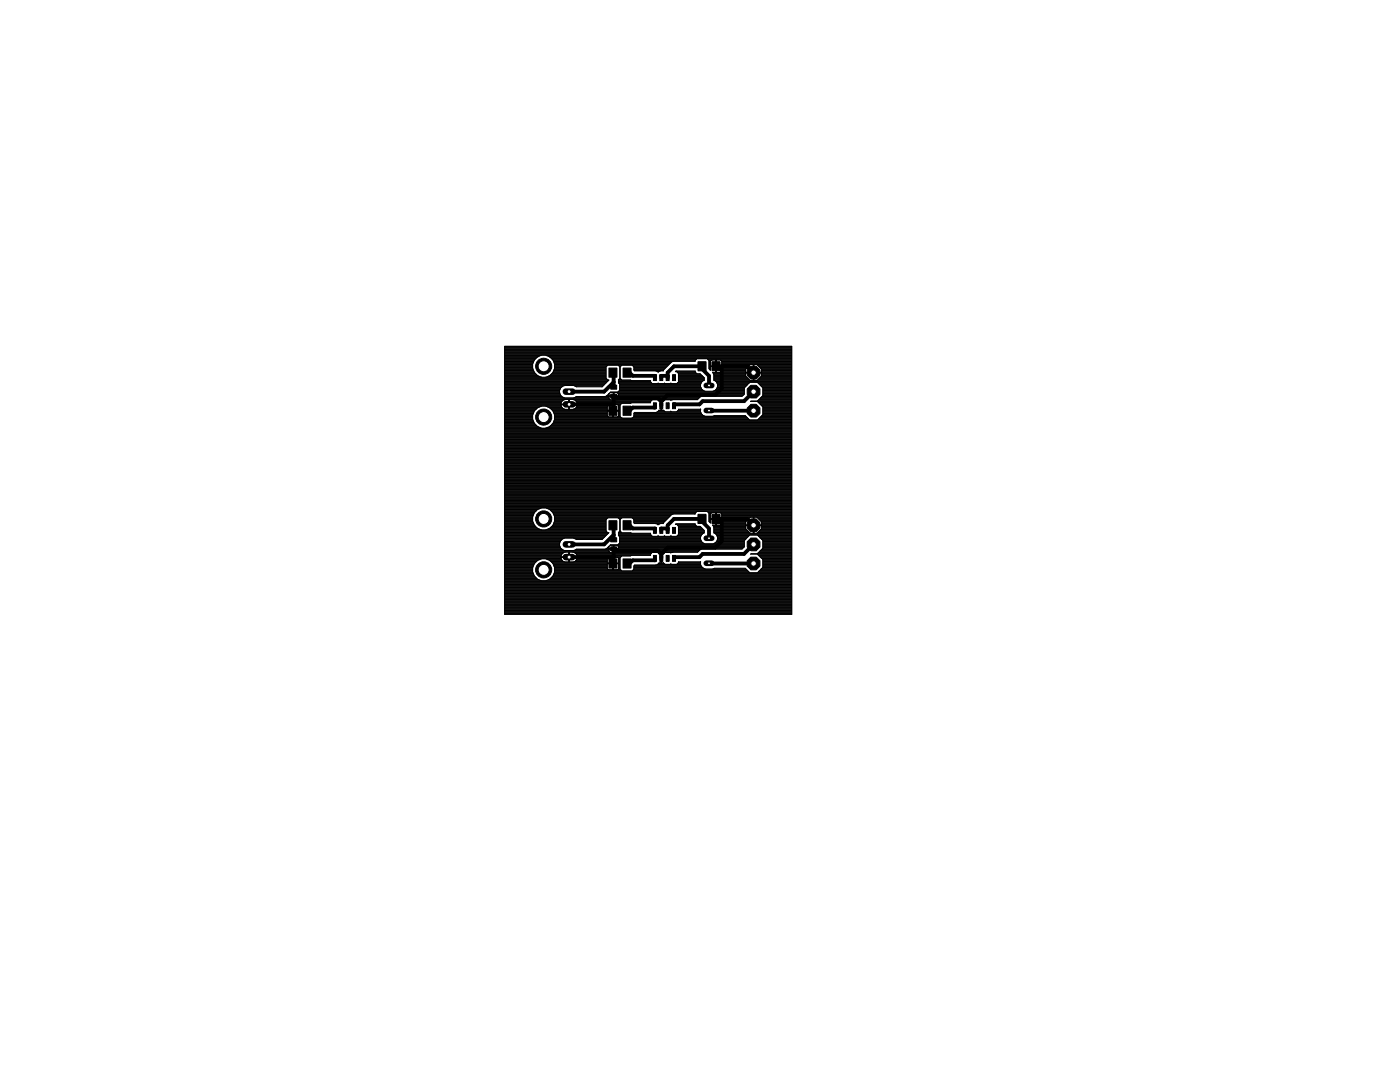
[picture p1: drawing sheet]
<svg xmlns="http://www.w3.org/2000/svg" width="279mm" height="216mm" viewBox="0 0 279 216" stroke-linecap="round" stroke-linejoin="round" font-family="sans-serif">
<g fill="#000" stroke="#000" stroke-width=".2">
<path d="M121.5 73.4h1.6v1.9h-1.6zM121.9 78.7h1.2v.8h-1.2zM121.9 76.9h1.2v.8h-1.2zM124.3 73.4h1.6v1.9h-1.6zM130.4 74.8h.6v1.1h-.6zM131.7 74.8h.6v1.1h-.6zM132.9 74.8h.6v1.1h-.6zM134.2 74.8h.6v1.1h-.6zM139.3 72.2h1.6v1.8h-1.6zM142.1 72.2h1.6v1.8h-1.6zM121.5 81h1.6v1.9h-1.6zM124.3 81h1.6v1.9h-1.6z"/>
<path d="M130.4 80.4h.6v1.2h-.6zM131.7 80.4h.6v1.2h-.6zM132.9 80.4h.6v1.2h-.6zM134.2 80.4h.6v1.2h-.6zM121.5 103.9h1.6v1.8h-1.6zM121.5 111.5h1.6v1.8h-1.6zM121.9 109.1h1.2v.8h-1.2zM121.9 107.3h1.2v.8h-1.2zM124.3 103.9h1.6v1.8h-1.6zM124.3 111.5h1.6v1.8h-1.6zM130.4 110.8h.6v1.2h-.6zM130.4 105.2h.6v1.2h-.6z"/>
<path d="M131.7 110.8h.6v1.2h-.6zM131.7 105.2h.6v1.2h-.6zM132.9 110.8h.6v1.2h-.6zM132.9 105.2h.6v1.2h-.6zM134.2 110.8h.6v1.2h-.6zM134.2 105.2h.6v1.2h-.6zM139.3 102.6h1.6v1.9h-1.6zM142.1 102.6h1.6v1.9h-1.6z"/>
<circle cx="150.4" cy="82" r="1.38"/>
</g>
<g fill="none" stroke="#000" stroke-width=".76">
<path d="M122.3 74.4h.2v2.9M122.5 79.1v2.9h-.2M122.5 79.4h8.8l.7 .7M122.5 76.3l-1.9 1.8h-7M125.1 74.4h.5l.7 .6h4.4v.4M133.2 75h-1.2v.4M139.6 73.1l1.9 1.9v1.9M140.1 73.1h-5.6l-1.3 1.3v1M142.9 73.1h6.2l1.3 1.3M144 73.1v4.4l-1.2 1.3h-9.6l-1.2 1.3M150.4 78.1l-1.9 2h-8.3l-.6 .6h-5.1v.3M113.6 80.7h8.9"/>
<path d="M130.7 81v.3h-4.4l-.7 .7h-.5M132 80.1v.9M141.5 81.9l8.9 .1M113.6 111.2h8.9M122.3 104.8h.2v2.9M122.5 109.5v2.9h-.2M122.5 109.9h8.8l.7 .6M122.5 106.7l-1.9 1.9h-7M125.1 104.8h.5l.7 .7h4.4v.3M130.7 111.4v.4h-4.4l-.7 .6h-.5M132 110.5v.9M133.2 105.5h-1.2v.3"/>
<path d="M139.6 103.5l1.9 2v1.9M140.1 103.5h-5.6l-1.3 1.3v1M141.5 112.4h8.9M142.9 103.5h6.2l1.3 1.3M144 103.5v4.5l-1.2 1.3h-9.6l-1.2 1.2M150.4 108.6l-1.9 1.9h-8.3l-.6 .7h-5.1v.2"/>
</g>
<g fill="none" stroke="#000" stroke-width=".2">
<path d="M100.7 69.1h57.3v53.5h-57.3zM100.7 79.7h12.1M100.7 73h5.6M100.7 74.1h5.8M100.7 72.9h5.6M100.7 74.2h5.9M100.7 74.3h5.9M100.7 72.7h5.6M100.7 74.4h6M100.7 75.3h20.2M100.7 79h11.3M100.7 79.1h11.4"/>
<path d="M100.7 77.2h11.4M100.7 80h11.6M100.7 79.8h11.7M100.7 79.6h20.9M100.7 79.5h20.8M100.7 79.4h11.9M100.7 79.2h11.6M100.7 78.9h11.2M100.7 78.8h11.1M100.7 78.6h11.1M100.7 78.5h11M100.7 78.4h11"/>
<path d="M100.7 78.3h11M100.7 78.2h11M100.7 78h11M100.7 77.9h11M100.7 77.8h11M100.7 77.7h11.1M100.7 77.6h11.1M100.7 77.4h11.2M100.7 77.3h11.3M100.7 77.1h11.6M100.7 77h11.9M100.7 76.8h19.8"/>
<path d="M100.7 76.7h19.9M100.7 76.6h20.1M100.7 76.5h20.2M100.7 76.3h20.3M100.7 76.2h20.4M100.7 76.1h20.5M100.7 76h20.7M100.7 75.8h20.5M100.7 75.6h20.4M100.7 75.5h20.3M100.7 75.4h20.2M100.7 75.1h7.1"/>
<path d="M100.7 75h6.8M100.7 74.9h6.5M100.7 74.8h6.4M100.7 74.7h6.3M100.7 74.5h6.1M100.7 73.9h5.8M100.7 73.8h5.7M100.7 73.7h5.7M100.7 73.6h5.6M100.7 73.4h5.6M100.7 73.3h5.6M100.7 73.2h5.6"/>
<path d="M100.7 73.1h5.6M100.7 72.6h5.6M100.7 72.5h5.7M100.7 72.4h5.7M100.7 72.2h5.8M100.7 72.1h5.8M100.7 72h5.9M100.7 71.9h5.9M100.7 71.8h6M100.7 71.6h6.1M100.7 71.5h6.3M100.7 71.4h6.4"/>
<path d="M100.7 71.3h6.5M100.7 71.2h6.7M100.7 71h7M100.7 70.9h7.3M100.7 70.8h57.3M100.7 70.7h57.3M100.7 70.6h57.3M100.7 70.4h57.3M100.7 70.3h57.3M100.7 70.2h57.3M100.7 70.1h57.3M100.7 70h57.3"/>
<path d="M100.7 69.8h57.3M100.7 69.7h57.3M100.7 69.6h57.3M100.7 69.5h57.3M100.7 69.4h57.3M100.7 69.2h57.3M108.1 75.3a2.23 2.23 0 0 1-1.5-3.5 2.23 2.23 0 0 1 3.7 0 2.23 2.23 0 0 1-1.4 3.5M109 70.9h49M109.2 75.1h11.7M109.3 71h48.7M109.5 75h11.4M109.6 71.2h48.4"/>
<path d="M109.8 74.9h11.1M109.8 71.3h48.2M109.9 74.8h11M109.9 71.4h48.1M110 74.7h10.9M110 71.5h48M110.1 74.5h10.8M110.2 71.6h28.8M110.3 74.4h10.6M110.3 71.8h28.6M110.4 74.3h10.5M110.4 71.9h28.4"/>
<path d="M110.4 74.2h10.5M110.4 72h28.3M110.5 74.1h10.4M110.5 72.1h23.8M110.5 73.9h10.4M110.5 72.2h23.5M110.6 73.8h10.3M110.6 72.4h23.3M110.6 73.7h10.3M110.6 72.5h23.2M110.7 73.6h10.2M110.7 73h10.5"/>
<path d="M110.7 72.9h22.7M110.7 72.7h22.8M110.7 73.4h10.2M110.7 73.3h10.2M110.7 73.2h10.2M110.7 73.1h10.4M110.7 72.6h22.9M111.7 77.9v.5M111.7 78.4l.2 .5 .8 .5h1.8l.5-.3h25M113.5 79.7v2M113.5 80h.1M113.5 79.8h.1"/>
<path d="M113.6 79.7v2M114.4 79.7h7.3M114.6 79.4h6.9M114.6 77h5.8M114.7 79.8l-1.9-.1-.6 .4M114.7 79.8l.3 .3M114.7 79.8h15.4M114.9 79.2h6.6M114.9 77.1h5.4M114.9 80h15.1M120.9 73.2v2.3l.4 .3M121 79h27.2"/>
<path d="M121.2 78.9h.3M121.3 72.9l-.4 .3M121.3 78.8h.2M121.4 78.6h.1M121.5 75.8v.1M121.5 75.8l-20.8 .1M121.5 75.9l-1.3 1.3h-5.2l-.5-.3h-1.8l-.8 .5-.2 .5M121.5 78.6v.4M121.5 79.1v.4M121.5 79.5l.2 .2M121.6 78.5l-.8 .6M121.6 78.5h.1"/>
<path d="M121.6 78.5l-.1 .1M121.7 78.4l.7-.1v1.5l-.7-.1M121.7 78.4h.1M121.8 78.3h26.7M122.4 79.7h.1M122.4 79.6h.1M122.4 79.5h.1M122.4 79.4h.1M122.4 79.2h.1M122.4 78.9h.1M122.4 78.8h.1M122.4 78.6h.1"/>
<path d="M122.4 78.5h.1M122.4 78.4h.1M123.3 78.4l-.8-.1v1.5h.7l.2-.3M123.3 78.4l.1 .1M123.3 78.4h25.2M123.4 78.5v.1M123.4 79.6h15.9M123.4 78.5h25.1M123.4 72.9l.3 .3M123.4 78.2h25.1M123.4 78.6v.4M123.4 79.1v.4"/>
<path d="M123.4 79.5h16M123.4 79.4h16.2M123.4 79.2h16.3M123.4 78.9h24.9M123.4 78.8h25M123.4 78.6h25.1M123.4 75.9h2.5M123.4 76.3h6.6M123.4 76.2h6.5M123.4 76.1h6.4M123.4 76h6.4M123.5 75.8h.5"/>
<path d="M123.5 73h.5M123.5 78h17.2M123.5 76.5h6.6M123.6 75.6h.3M123.6 73.1h.3M123.6 76.6h16.3M123.6 77.9h16.8M123.7 77.2h16.1M123.7 77.8h16.5M123.7 77.7h16.4M123.7 77.6h16.3M123.7 77.4h16.2"/>
<path d="M123.7 77.3h16.2M123.7 77.1h16.1M123.7 77h16.1M123.7 76.8h16.1M123.7 76.7h16.1M123.7 75.5h.1M123.7 73.2v2.3M123.7 75.5l-.3 .3v.6l.3 .2v1.3l-.4 .3h-1.5l-.1 .2M123.7 74.1h.1M123.7 74.2h.1M123.7 74.3h.1M123.7 74.4h.1"/>
<path d="M123.7 75.3h.1M123.7 75.4h.1M123.7 75.1h.1M123.7 75h.1M123.7 74.9h.1M123.7 74.8h.1M123.7 74.7h.1M123.7 74.5h.1M123.7 73.9h.1M123.7 73.8h.1M123.7 73.7h.1M123.7 73.6h.1"/>
<path d="M123.7 73.4h.1M123.7 73.3h.1M123.7 73.2h.1M123.7 75.5l.4 .3M124.1 72.9l-.4 .3M126.2 72.9l.3 .3M126.3 73h7M126.4 73.1h6.7M126.5 73.2v.7l.2 .1h4.2l.4 .2M126.5 73.8h5.9M126.5 73.7h6M126.5 73.6h6.2"/>
<path d="M126.5 73.4h6.3M126.5 73.3h6.4M126.5 73.2h6.5M126.6 73.9h5.8M131 74.1h.7M131.3 74.2h.1M131.3 76.5h.1M131.3 79.8h1.3M131.4 80h1.1M132.4 73.8v.2l-1.1 .2M132.6 76.5h.1M133.9 76.5h.1"/>
<path d="M133.9 79.8h.1M134.3 79.7l-.4 .2-1.2-.1-.3 .3M134.8 74.2l.1-.2h3.8v.2zM135.1 74.2l.3 .3v1.7l-.3 .3h-4.9l-.4-.3v-.3l-4-.1M135.1 76.5h4.8M135.2 74.3h3.6M135.3 76.3h4.7M135.3 74.4h3.6M135.4 76.2h4.6M135.4 75.9h5.1M135.4 75.3h5M135.4 76.1h4.8"/>
<path d="M135.4 76h4.9M135.4 75.8h5.1M135.4 75.6h5.1M135.4 75.5h5.1M135.4 75.4h5.1M135.4 75.1h4.9M135.4 75h4.8M135.4 74.9h4.7M135.4 74.8h4.5M135.4 74.7h4.4M135.4 74.5h3.6M138.7 74.2l.4 .4h.6l.8 .8"/>
<path d="M139.7 79.2l-.5 .5h-15.9M139.8 76.7a1.18 1.18 0 0 0 .9 1.4h1.6a1.14 1.14 0 0 0 .9-1.4M140.3 76l-.5 .7M140.5 75.4v.5M140.5 75.9l-.2 .1M141.2 71.6h16.8M141.3 71.8h16.7M141.4 71.9h.5M141.5 73.6l.3 .3v-.7h2.2v.8M141.5 73h8M141.5 73.6v-1.7l-.4-.3h-2l-.4 .5h-4.4l-.3 .2-1.6 1.5M141.5 72.9h.3"/>
<path d="M141.5 72.7h.3M141.5 73.6h.3M141.5 73.4h.3M141.5 73.3h.3M141.5 73.2h.3M141.5 73.1h1.3M141.5 72.6h.3M141.5 72.5h.3M141.5 72.4h.3M141.5 72.2h.3M141.5 72.1h.3M141.5 72h.3"/>
<path d="M141.6 73.7h.2M141.7 73.8h.1M141.8 72.1l.3-.3h.7v2.5h-.6l.3 .5M141.8 72.1v.9M142.3 74.4h15.7M142.3 78h6.2M142.4 74.5h6.4M142.4 74.7h6.4M142.5 75.9h7.1M142.5 75.9l.5 .4 .2 .4M142.5 74.8v1.1M142.5 75.3h6.6"/>
<path d="M142.5 75.8h7M142.5 75.6h6.9M142.5 75.5h6.8M142.5 75.4h6.7M142.5 75.1h6.4M142.5 75h6.3M142.5 74.9h6.3M142.5 74.8h6.3M142.6 77.9h5.9M142.7 76h15.3M142.8 77.8h5.7M142.8 74.1h.2"/>
<path d="M142.8 72.9h.2M142.8 74.2h.2M142.8 74.3h.2M142.8 72.7h.2M142.8 73.9h.2M142.8 73.8h.2M142.8 73.7h.2M142.8 73.6h.2M142.8 73.4h.2M142.8 73.3h.2M142.8 73.2h.2M142.8 72.6h.2"/>
<path d="M142.8 72.5h.2M142.8 72.4h.2M142.8 72.2h.2M142.8 72.1h.2M142.8 72h.2M142.8 71.9h.2M142.9 76.1h15.1M142.9 77.7h5.6M143 76.2h15M143 73.1h6.4M143 77.6h5.5M143 76.3h6.6"/>
<path d="M143.1 77.4h5.4M143.1 76.5h6.4M143.1 77.3h5.5M143.2 76.6h6.1M143.2 77.2h5.5M143.2 77.1h5.7M143.2 77h5.8M143.2 76.8h5.9M143.2 76.7h6M143.8 74.3h14.2M143.8 71.9h14.2M144 74.2h4.8"/>
<path d="M144 72h14M144 74.1h4.8M144 72.1l-.3-.3h-.7v2.5l1-.1M144 74v.2M144 72.1v.9M144 72.9h5.6M144 72.7h14M144 73.9h4.8M144 73.8h4.8M144 73.7h4.8M144 73.6h4.9M144 73.4h5"/>
<path d="M144 73.3h5.1M144 73.2h5.3M144 72.6h14M144 72.5h14M144 72.4h14M144 72.2h14M144 72.1h14M148.5 78.7v-1.3l1.1-1.1h1.6l1.1 1.1v1.5l-1.1 1.1-1.4 .1h1.4l1.1 1.1v1.5l-1.1 1.1M148.5 78.7l-.4 .4h-8.1l-.3 .1M148.8 73.7v.6M148.8 74.4v.6M149.7 72.7l-.9 1"/>
<path d="M150.3 72.7v3.2h-.6l-.9-.9M150.3 73h.2M150.3 74.1h.2M150.3 72.9h.2M150.3 75.9h.2M150.3 74.2h.2M150.3 75.3h.2M150.3 75.8h.2M150.3 75.6h.2M150.3 75.5h.2M150.3 75.4h.2M150.3 75.1h.2"/>
<path d="M150.3 75h.2M150.3 74.9h.2M150.3 74.8h.2M150.3 74.7h.2M150.3 74.5h.2M150.3 73.9h.2M150.3 73.8h.2M150.3 73.7h.2M150.3 73.6h.2M150.3 73.4h.2M150.3 73.3h.2M150.3 73.2h.2"/>
<path d="M150.3 73.1h.2M150.5 72.7v3.2h.5l1-.9M151 72.7l1 1M151.1 75.9h6.9M151.2 72.9h6.8M151.2 80h6.8M151.2 76.3h6.8M151.3 75.8h6.7M151.3 73h6.7M151.3 79.8h6.7M151.3 76.5h6.7M151.4 75.6h6.6"/>
<path d="M151.4 73.1h6.6M151.4 79.7h6.6M151.4 76.6h6.6M151.5 75.5h6.5M151.5 73.2h6.5M151.6 79.6h6.4M151.6 76.7h6.4M151.6 75.4h6.4M151.6 73.3h6.4M151.7 79.5h6.3M151.7 76.8h6.3M151.7 75.3h6.3"/>
<path d="M151.8 73.4h6.2M151.8 79.4h6.2M151.8 77h6.2M151.8 75.1h6.2M151.9 73.6h6.1M151.9 79.2h6.1M151.9 77.1h6.1M152 75h6M152 73.7v.6M152 74.4v.6M152 74.1h6M152 74.2h6"/>
<path d="M152 74.9h6M152 74.8h6M152 74.7h6M152 74.5h6M152 73.9h6M152 73.8h6M152 73.7h6M152 79.1h6M152 77.2h6M152.2 79h5.8M152.2 77.3h5.8M152.3 78.9h5.7"/>
<path d="M152.3 78.8h5.7M152.3 78.6h5.7M152.3 78.5h5.7M152.3 78.4h5.7M152.3 78.3h5.7M152.3 78.2h5.7M152.3 78h5.7M152.3 77.9h5.7M152.3 77.8h5.7M152.3 77.7h5.7M152.3 77.6h5.7M152.3 77.4h5.7"/>
<path d="M100.7 80.5h11.3M100.7 82.3h5.8M100.7 81.9h6M100.7 81h11.3M100.7 82.1h5.9M100.7 81.7h6.3M100.7 83.8h5.7M100.7 82h5.9M100.7 100h57.3M100.7 99.9h57.3M100.7 99.7h57.3M100.7 99.6h57.3"/>
<path d="M100.7 99.5h57.3M100.7 99.4h57.3M100.7 99.3h57.3M100.7 99.1h57.3M100.7 99h57.3M100.7 98.9h57.3M100.7 98.8h57.3M100.7 98.7h57.3M100.7 98.5h57.3M100.7 98.4h57.3M100.7 98.3h57.3M100.7 98.2h57.3"/>
<path d="M100.7 98h57.3M100.7 97.9h57.3M100.7 97.8h57.3M100.7 97.7h57.3M100.7 97.6h57.3M100.7 97.5h57.3M100.7 97.3h57.3M100.7 97.2h57.3M100.7 97.1h57.3M100.7 97h57.3M100.7 96.9h57.3M100.7 96.7h57.3"/>
<path d="M100.7 96.6h57.3M100.7 96.5h57.3M100.7 96.4h57.3M100.7 96.2h57.3M100.7 96.1h57.3M100.7 96h57.3M100.7 95.9h57.3M100.7 95.8h57.3M100.7 95.7h57.3M100.7 95.5h57.3M100.7 95.4h57.3M100.7 95.3h57.3"/>
<path d="M100.7 95.2h57.3M100.7 95h57.3M100.7 94.9h57.3M100.7 94.8h57.3M100.7 94.7h57.3M100.7 94.6h57.3M100.7 94.4h57.3M100.7 94.3h57.3M100.7 94.2h57.3M100.7 94.1h57.3M100.7 94h57.3M100.7 93.8h57.3"/>
<path d="M100.7 93.7h57.3M100.7 93.6h57.3M100.7 93.5h57.3M100.7 93.3h57.3M100.7 93.2h57.3M100.7 93.1h57.3M100.7 93h57.3M100.7 92.9h57.3M100.7 92.8h57.3M100.7 92.6h57.3M100.7 92.5h57.3M100.7 92.4h57.3"/>
<path d="M100.7 92.3h57.3M100.7 92.1h57.3M100.7 92h57.3M100.7 91.9h57.3M100.7 91.8h57.3M100.7 91.7h57.3M100.7 91.5h57.3M100.7 91.4h57.3M100.7 91.3h57.3M100.7 91.2h57.3M100.7 91.1h57.3M100.7 90.9h57.3"/>
<path d="M100.7 90.8h57.3M100.7 90.7h57.3M100.7 90.6h57.3M100.7 90.5h57.3M100.7 90.3h57.3M100.7 90.2h57.3M100.7 90.1h57.3M100.7 90h57.3M100.7 89.9h57.3M100.7 89.7h57.3M100.7 89.6h57.3M100.7 89.5h57.3"/>
<path d="M100.7 89.4h57.3M100.7 89.3h57.3M100.7 89.1h57.3M100.7 89h57.3M100.7 88.9h57.3M100.7 88.8h57.3M100.7 88.6h57.3M100.7 88.5h57.3M100.7 88.4h57.3M100.7 88.3h57.3M100.7 88.2h57.3M100.7 88.1h57.3"/>
<path d="M100.7 87.9h57.3M100.7 87.8h57.3M100.7 87.7h57.3M100.7 87.6h57.3M100.7 87.4h57.3M100.7 87.3h57.3M100.7 87.2h57.3M100.7 87.1h57.3M100.7 87h57.3M100.7 86.8h57.3M100.7 86.7h57.3M100.7 86.6h57.3"/>
<path d="M100.7 86.5h57.3M100.7 86.4h57.3M100.7 86.2h57.3M100.7 86.1h57.3M100.7 86h57.3M100.7 85.9h57.3M100.7 85.7h57.3M100.7 85.6h57.3M100.7 85.5h57.3M100.7 85.4h7.3M100.7 85.3h7M100.7 85.2h6.7"/>
<path d="M100.7 85h6.5M100.7 84.9h6.4M100.7 84.8h6.3M100.7 84.7h6.1M100.7 84.5h6M100.7 84.4h5.9M100.7 84.3h5.9M100.7 84.2h5.8M100.7 84.1h5.8M100.7 83.9h5.7M100.7 83.7h5.6M100.7 83.6h5.6"/>
<path d="M100.7 83.5h5.6M100.7 83.3h5.6M100.7 83.2h5.6M100.7 83.1h5.6M100.7 83h5.6M100.7 82.9h5.6M100.7 82.7h5.6M100.7 82.6h5.7M100.7 82.5h5.7M100.7 82.4h5.8M100.7 81.8h6.1M100.7 81.5h6.4"/>
<path d="M100.7 81.4h6.5M100.7 81.3h6.8M100.7 81.2h7.1M100.7 80.9h11.3M100.7 80.8h11.3M100.7 80.7h12.8M100.7 80.6h11.3M100.7 80.3h11.3M100.7 80.2h11.4M100.7 80.1h11.4M106.6 82a2.24 2.24 0 0 0 1.9 3.5 2.24 2.24 0 0 0 1.9-3.5M108.1 81l-.8 .4-.7 .6"/>
<path d="M108.9 81l.8 .4 .7 .6M109 85.4h49M109.2 81.2h2.9M109.3 85.3h48.7M109.5 81.3h2.6M109.6 85.2h48.4M109.8 81.4h2.4M109.8 85h48.2M109.9 81.5h2.5M109.9 84.9h48.1M110 81.7h2.7M110 84.8h48"/>
<path d="M110.1 81.8h11.1M110.2 84.7h47.8M110.3 81.9h13.4M110.3 84.5h47.7M110.4 82h13.3M110.4 84.4h47.6M110.4 82.1h10.8M110.4 84.3h47.6M110.5 82.3h10.7M110.5 84.2h47.5M110.5 82.4h10.7M110.5 84.1h47.5"/>
<path d="M110.6 83.9h47.4M110.6 82.5h10.6M110.6 83.8h47.4M110.6 82.6h10.6M110.7 82.7h10.5M110.7 83.7h38.8M110.7 83.6h38.7M110.7 83.5h38.6M110.7 83.3h13.3M110.7 83.2h13.2M110.7 83.1h10.6M110.7 83h10.5"/>
<path d="M110.7 82.9h10.5M111.9 80.6h.1M111.9 80.8h.1M111.9 80.6h3.3M111.9 80.8h3.3M111.9 80.8l.2 .4M112.1 81.2l.1 .1M112.2 81.3l.6 .4h1.5l.7-.4M112.2 80.1l-.3 .5M113.5 80.5h.1M113.5 81h.1M113.5 81.5h.1"/>
<path d="M113.5 81.4h.1M113.5 81.3h.1M113.5 81.2h.1M113.5 80.9h.1M113.5 80.8h.1M113.5 80.6h.1M113.5 80.3h.1M113.5 80.2h.1M113.5 80.1h.1M113.6 80.7h10.3M114.4 81.7h6.8M114.7 81.5h6.5"/>
<path d="M114.9 81.4h6.3M115 80.1l.2 .5M115 80.1h14.9M115 81.3h6.2M115.1 80.2h14.7M115.1 81.2l-.1 .1M115.1 81.2h6.1M115.1 81h6.1M115.1 80.3h14.7M115.2 80.5h10.7M115.2 80.9h6M115.2 80.8l-.1 .4"/>
<path d="M115.2 80.6h.1M115.2 80.8h.1M115.2 80.8h6.1M115.2 80.6h8.8M121.2 81v.9M121.2 82v1M121.2 80.9l.3-.2h.8v2.5h-.8l-.3-.2M121.2 80.9v.1M122.3 82.3h.1M122.3 81h.1M122.3 82.1h.1M122.3 81.7h.1"/>
<path d="M122.3 83.1h.1M122.3 83h.1M122.3 82.9h.1M122.3 82.7h.1M122.3 82.6h.1M122.3 82.5h.1M122.3 82.4h.1M122.3 81.8h.1M122.3 81.5h.1M122.3 81.4h.1M122.3 81.3h.1M122.3 81.2h.1"/>
<path d="M122.3 80.9h.1M122.3 80.8h.1M123.3 80.8h.5M123.4 83.1h.3M123.4 80.9l-.2-.2h-.8v2.5l.9-.1M123.4 83l-.1 .1M123.4 80.9l.1 .1M123.4 83h.3M123.4 80.9h.3M123.5 81v.9M123.5 82l-.1 1M123.5 82.3h.2"/>
<path d="M123.5 81h.2M123.5 82.1h.2M123.5 81.7h.2M123.5 82.9h.2M123.5 82.7h.2M123.5 82.6h.2M123.5 82.5h.2M123.5 82.4h.2M123.5 81.8h.2M123.5 81.5h.2M123.5 81.4h.2M123.5 81.3h.2"/>
<path d="M123.5 81.2h.2M123.7 83.1l.4 .3h2.1l.3-.3M124.1 80.5l-.4 .3v2.3M126.3 83.3h22.8M126.4 83.2h22.6M126.5 83.1h22.4M126.5 83h14M126.5 82.9h13.8M126.5 82.7h13.7M126.5 82.6h13.5M126.5 82.5h13.5M126.6 82.4h13.3"/>
<path d="M131 82.3h8.8M131.3 82.1l-.4 .2h-4.2l-.2 .1v.7M131.3 82.1h8.5M131.4 82h1.2M131.5 81.9h1M131.6 80.1l.3-.1v.9h.2v-.9l.3 .1M131.6 81.9h.1M131.6 80.1l-.3-.3h-1.1l-.4 .3v.3l-4 .1M131.6 80.1h.1M131.6 81.9l-.3 .2M131.9 81.9v-.9h.2v.9M131.9 80.5h.2"/>
<path d="M131.9 81.7h.2M131.9 81.8h.2M131.9 81.5h.2M131.9 81.4h.2M131.9 81.3h.2M131.9 81.2h.2M131.9 80.8h.2M131.9 80.7h.2M131.9 80.6h.2M131.9 80.3h.2M131.9 80.2h.2M131.9 80.1h.2"/>
<path d="M132.4 81.9h.1M132.4 81.9h-.1M132.4 81.9l.3 .2M132.4 80.1h.1M133.8 82.1l.1-.1 .1 .1M135.2 82h4.6M135.3 81.9h4.5M135.4 81.8l-.3 .3M135.4 81.8h4.4M139.8 81.7v.4M139.8 82.1l.5 .8 .4 .2 8-.2 .9 .9M139.8 81.7h-4.4v.1"/>
<path d="M142.5 83h6.3M149.8 80.1h8.2M151.3 80.2h6.7M151.3 83.7h6.7M151.4 80.3h6.6M151.4 83.6h6.6M151.5 80.5h6.5M151.5 83.5h6.5M151.6 80.6h6.4M151.6 83.3h6.4M151.7 80.7h6.3M151.8 83.2h6.2"/>
<path d="M151.8 80.8h6.2M151.9 83.1h6.1M152 80.9h6M152 83h6M152.1 81h5.9M152.1 82.9h5.9M152.2 82.7h5.8M152.2 81.2h5.8M152.3 82.3h5.7M152.3 81.9h5.7M152.3 82.1h5.7M152.3 81.7h5.7"/>
<path d="M152.3 82h5.7M152.3 82.6h5.7M152.3 82.5h5.7M152.3 82.4h5.7M152.3 81.8h5.7M152.3 81.5h5.7M152.3 81.4h5.7M152.3 81.3h5.7M100.7 110.2h11.9M100.7 110.8h11.3M100.7 111h11.3M100.7 112.8h5.8"/>
<path d="M100.7 110.5h11.5M100.7 115.9h57.3M100.7 109.9h20.8M100.7 109.6h11.5M100.7 108.8h11M100.7 103.2h5.6M100.7 104.9h6.1M100.7 111.2h23.1M100.7 112.5h5.9M100.7 103.6h5.6M100.7 103.5h5.6M100.7 111.1h23.3"/>
<path d="M100.7 112.2h6.2M100.7 120h57.3M100.7 119.9h57.3M100.7 119.8h57.3M100.7 119.6h57.3M100.7 119.5h57.3M100.7 119.4h57.3M100.7 119.3h57.3M100.7 119.1h57.3M100.7 119h57.3M100.7 118.9h57.3M100.7 118.8h57.3"/>
<path d="M100.7 118.7h57.3M100.7 118.6h57.3M100.7 118.4h57.3M100.7 118.3h57.3M100.7 118.2h57.3M100.7 118.1h57.3M100.7 117.9h57.3M100.7 117.8h57.3M100.7 117.7h57.3M100.7 117.6h57.3M100.7 117.5h57.3M100.7 117.3h57.3"/>
<path d="M100.7 117.2h57.3M100.7 117.1h57.3M100.7 117h57.3M100.7 116.9h57.3M100.7 116.8h57.3M100.7 116.6h57.3M100.7 116.5h57.3M100.7 116.4h57.3M100.7 116.3h57.3M100.7 116.1h57.3M100.7 116h57.3M100.7 115.8h7.1"/>
<path d="M100.7 115.7h6.8M100.7 115.5h6.5M100.7 115.4h6.4M100.7 115.3h6.3M100.7 115.2h6.2M100.7 115.1h6M100.7 114.9h5.9M100.7 114.8h5.9M100.7 114.7h5.8M100.7 114.6h5.8M100.7 114.4h5.7M100.7 114.3h5.7"/>
<path d="M100.7 114.2h5.6M100.7 114.1h5.6M100.7 114h5.6M100.7 113.9h5.6M100.7 113.7h5.6M100.7 113.6h5.6M100.7 113.5h5.6M100.7 113.4h5.6M100.7 113.2h5.6M100.7 113.1h5.7M100.7 113h5.7M100.7 112.9h5.8"/>
<path d="M100.7 112.6h5.9M100.7 112.4h6M100.7 112.3h6.1M100.7 112h6.4M100.7 111.9h6.5M100.7 111.8h6.7M100.7 111.7h7M100.7 111.6h7.2M100.7 111.4h11.3M100.7 111.3h11.3M100.7 110.7h11.3M100.7 110.6h11.4"/>
<path d="M100.7 110.4h11.7M100.7 110.1h20.9M100.7 110h20.8M100.7 109.7h11.7M100.7 109.5h11.4M100.7 109.4h11.2M100.7 109.3h11.1M100.7 109.2h11.1M100.7 109h11M100.7 108.9h11M100.7 108.7h11M100.7 108.5h11"/>
<path d="M100.7 108.4h11M100.7 108.3h11M100.7 108.2h11.1M100.7 108.1h11.1M100.7 107.9h11.2M100.7 107.8h11.3M100.7 107.7h11.4M100.7 107.6h11.5M100.7 107.5h11.8M100.7 107.3h19.8M100.7 107.2h19.9M100.7 107.1h20"/>
<path d="M100.7 107h20.1M100.7 106.8h20.3M100.7 106.7h20.4M100.7 106.6h20.5M100.7 106.5h20.6M100.7 106.4h20.7M100.7 106.3h20.5M100.7 106.1h20.4M100.7 106h20.3M100.7 105.9h20.2M100.7 105.8h20.2M100.7 105.6h7.1"/>
<path d="M100.7 105.5h6.9M100.7 105.4h6.6M100.7 105.3h6.4M100.7 105.2h6.3M100.7 105.1h6.2M100.7 104.8h6M100.7 104.7h5.9M100.7 104.6h5.9M100.7 104.4h5.8M100.7 104.3h5.7M100.7 104.2h5.7M100.7 104.1h5.6"/>
<path d="M100.7 104h5.6M100.7 103.8h5.6M100.7 103.7h5.6M100.7 103.4h5.6M100.7 103.1h5.6M100.7 103h5.7M100.7 102.9h5.7M100.7 102.8h5.7M100.7 102.6h5.8M100.7 102.5h5.9M100.7 102.4h5.9M100.7 102.3h6"/>
<path d="M100.7 102.2h6.1M100.7 102h6.2M100.7 101.9h6.3M100.7 101.8h6.4M100.7 101.7h6.6M100.7 101.6h6.9M100.7 101.4h7.2M100.7 101.3h57.3M100.7 101.2h57.3M100.7 101.1h57.3M100.7 100.9h57.3M100.7 100.8h57.3"/>
<path d="M100.7 100.7h57.3M100.7 100.6h57.3M100.7 100.5h57.3M100.7 100.4h57.3M100.7 100.2h57.3M100.7 100.1h57.3M106.3 113.3a2.23 2.23 0 0 1 2.2-1.8 2.23 2.23 0 0 1 2.2 1.8M106.3 113.3v.8l.3 .8M106.3 104l.3 .8 .7 .6M106.6 114.9l.7 .6 .8 .4M107.3 101.7l.8-.4h.8l.8 .4M107.3 101.7l-.7 .6-.3 .8v.9"/>
<path d="M107.3 105.4l.8 .3h.8l.8-.3M109.1 111.6h2.9M109.1 101.4h48.9M109.1 105.6h11.8M109.2 115.8h48.8M109.3 111.7h2.8M109.4 101.6h48.6M109.4 105.5h11.5M109.5 115.7h48.5M109.6 111.8h2.6M109.7 101.7h48.3M109.7 101.7l.7 .6 .3 .8v.9"/>
<path d="M109.7 105.4h11.2M109.7 115.5h48.3M109.8 111.9h2.5M109.8 101.8h48.2M109.9 105.3h11M109.9 115.4h48.1M109.9 112h2.6M110 101.9h48M110 105.2h10.9M110 115.3h48M110.1 112.2h11.1M110.1 105.1h10.8"/>
<path d="M110.1 102h47.9M110.1 115.2h47.9M110.2 112.3h11M110.2 104.9h10.7M110.2 102.2h28.8M110.2 115.1h47.8M110.3 112.4h12M110.3 102.3h28.6M110.3 104.8h10.6M110.4 114.9l-.7 .6-.8 .4M110.4 114.9h47.6M110.4 112.5h13.3"/>
<path d="M110.4 102.4h28.3M110.4 114.8h47.6M110.4 104.7h10.5M110.4 112.6h10.8M110.4 114.7h47.6M110.4 104.6h10.5M110.4 102.5h28.3M110.5 112.8h10.7M110.5 104.4h10.4M110.5 102.6h23.7M110.5 114.6h47.5M110.5 112.9h10.7"/>
<path d="M110.5 102.8h23.4M110.6 114.4h47.4M110.6 104.3h10.3M110.6 113h10.6M110.6 104.2h10.3M110.6 102.9h23.2M110.6 114.3h47.4M110.6 113.1h10.6M110.6 104.1h10.3M110.6 103h23.1M110.7 114.2h38.8M110.7 113.3v.8l-.3 .8"/>
<path d="M110.7 104l-.3 .8-.7 .6M110.7 103.2h22.8M110.7 103.6h10.3M110.7 103.5h10.4M110.7 114.1h38.7M110.7 114h38.6M110.7 113.9h13.3M110.7 113.7h13.2M110.7 113.6h10.6M110.7 113.5h10.5M110.7 113.4h10.5M110.7 113.2h10.5"/>
<path d="M110.7 104h10.2M110.7 103.8h10.2M110.7 103.7h10.2M110.7 103.4h10.6M110.7 103.1h22.9M111.9 111.1h.1M111.9 111.2l.1 .2M112 111.4l.3 .5M112.1 110.7l-.2 .4M112.2 107.6l.5-.2h1.8l.4 .2M112.2 107.6a1.26 1.26 0 0 0-.5 1.3 1.26 1.26 0 0 0 1 1M112.3 111.9l.2 .1"/>
<path d="M112.5 112l.3 .1M112.6 110.2h.9v1.9M112.6 110.2l-.5 .5M113.5 110.2h.1M113.5 110.8h.1M113.5 111h.1M113.5 110.5h.1M113.5 112h.1M113.5 111.9h.1M113.5 111.8h.1M113.5 111.7h.1M113.5 111.6h.1"/>
<path d="M113.5 111.4h.1M113.5 111.3h.1M113.5 110.7h.1M113.5 110.6h.1M113.5 110.4h.1M114.6 110.2h7.2M114.7 107.5h5.7M114.7 112h6.5M114.7 112l-.4 .1M114.7 109.7h6.8M114.8 110.4h15.2M114.9 111.9l-.2 .1"/>
<path d="M114.9 111.9h6.3M114.9 110.5h15M114.9 107.6h5.3M115 109.6h24.9M115 111.8h6.2M115 110.6h14.8M115.1 111.7h6.1M115.1 110.7l-.6-.5h-.9v1.9M115.1 110.7l.1 .4M115.1 110.7h14.7M115.1 111.6h6.1M115.2 111.4l-.3 .5"/>
<path d="M115.2 111.4h6M115.2 111.1h.1M115.2 111.2v.2M115.2 111.3h6.1M120.9 109.5h1.5M121.2 109.4h.3M121.2 112.5v.9M121.2 113.4l.1 .2M121.3 109.3h.2M121.4 109.2h.1M121.5 111.2l-.3 .2v1h2.3l-.1-1-.2-.2M121.5 106.3h.1"/>
<path d="M121.5 106.3l-1.3 1.4-5.3-.1M121.5 109h.1M121.5 109.6v.4M121.5 110l.1 .1M121.6 109l-.8 .6h-5.8l-.5 .3M121.6 109h.1M121.6 110.1l.1 .1M121.7 108.8h.1M121.8 108.8h26.7M121.8 108.8h-.1M122.3 112.8h.1M122.3 111.2v2.5l-1-.1"/>
<path d="M122.3 112.2h.1M122.3 113.6h.1M122.3 113.5h.1M122.3 113.4h.1M122.3 113.2h.1M122.3 113.1h.1M122.3 113h.1M122.3 112.9h.1M122.3 112.6h.1M122.3 112.3h.1M122.3 112h.1M122.3 111.9h.1"/>
<path d="M122.3 111.8h.1M122.3 111.7h.1M122.3 111.6h.1M122.3 111.4h.1M122.3 111.3h.1M122.4 110.2h.1M122.4 109.9h.1M122.4 108.8v1.5l-.7-.1M122.4 110.1h.1M122.4 110h.1M122.4 109.7h.1M122.4 109.4h.1"/>
<path d="M122.4 109.3h.1M122.4 109.2h.1M122.4 109h.1M122.4 108.9h.1M122.4 111.2v2.5l.9-.1M122.4 112.4h1.3M122.5 108.8v1.5l.7-.1M122.5 109.5h25.6M123.1 108.8l.3 .3v.4h-1.9l.1-.5M123.3 110.1l-.1 .1M123.3 113.6h.5M123.3 108.9h25.2"/>
<path d="M123.3 110.1h16M123.3 108.7h25.2M123.4 111.3h.3M123.4 110h16M123.4 109h25.1M123.4 109.9h16.1M123.4 110l-.1 .1M123.4 109.6v.4M123.4 109.7h16.3M123.4 109.4h24.9M123.4 109.3h25M123.4 109.2h25.1"/>
<path d="M123.4 103.4h.7M123.4 106.9l.3 .2v1.3l-.4 .3-1.6 .1M123.4 113.5h.3M123.4 106.8h6.6M123.4 106.7h6.5M123.4 106.6h6.4M123.4 106.5h6.4M123.4 106.4h2.6M123.4 106.3h.6M123.4 111.4h.3M123.5 112.8h.2M123.5 113.4l-.2 .2"/>
<path d="M123.5 112.5v.9M123.5 112.2h.2M123.5 113.4h.2M123.5 113.2h.2M123.5 113.1h.2M123.5 113h.2M123.5 112.9h.2M123.5 112.6h.2M123.5 112.3h.2M123.5 112h.2M123.5 111.9h.2M123.5 111.8h.2"/>
<path d="M123.5 111.7h.2M123.5 111.6h.2M123.5 108.5h25M123.5 103.5h.4M123.5 106.1h.4M123.5 107h6.6M123.6 108.4h16.9M123.6 103.6h.2M123.7 108.3h16.6M123.7 108.2h16.4M123.7 108.1h16.3M123.7 107.9h16.3"/>
<path d="M123.7 107.8h16.2M123.7 107.7h16.1M123.7 107.6h16.1M123.7 107.5h16.1M123.7 107.3h16.1M123.7 107.2h16.1M123.7 107.1h16.1M123.7 106h.1M123.7 103.7v2.3M123.7 103.7l-.3-.4h-2.1l-.4 .4v2.3l.4 .3h.2M123.7 106l-.3 .2v.7M123.7 104.9h.1"/>
<path d="M123.7 105.9h.1M123.7 105.8h.1M123.7 105.6h.1M123.7 105.5h.1M123.7 105.4h.1M123.7 105.3h.1M123.7 105.2h.1M123.7 105.1h.1M123.7 104.8h.1M123.7 104.7h.1M123.7 104.6h.1M123.7 104.4h.1"/>
<path d="M123.7 104.3h.1M123.7 104.2h.1M123.7 104.1h.1M123.7 104h.1M123.7 103.8h.1M123.7 103.7h.1M123.7 111.3v2.3l.4 .3h2.1l.3-.3v-.7l.2-.1h13.2M123.7 103.7l.4-.4h2.1l.3 .4v.6M124.1 111l-.4 .3M126.1 110.8l-.3 .2h-10.6M126.2 103.4h7.1M126.2 113.9h23"/>
<path d="M126.3 103.5h6.9M126.4 113.7h22.7M126.4 103.6h6.7M126.5 113.6h22.4M126.5 113.5h14.1M126.5 113.4h13.8M126.5 113.2h13.7M126.5 113.1h13.6M126.5 113h13.5M126.5 104.3h5.9M126.5 104.2h6M126.5 104.1h6.1"/>
<path d="M126.5 104h6.2M126.5 103.8h6.4M126.5 103.7h6.5M126.6 112.9h13.3M126.6 104.4h5.8M130.2 110.2l-.4 .4v.2h-14.6M131.1 104.6h.5M131.2 112.6h8.6M131.3 110.2l.3 .3M131.3 107h.1M131.3 104.7h.1M131.4 112.5h1.2"/>
<path d="M131.4 110.4h1.2M131.5 112.4h1M131.5 110.5h1M131.6 110.5h.3v.9h.2v-.9h.3M131.6 112.3l.3 .1v-.9h.2v.9l.3-.1M131.6 110.5h.1M131.6 112.3l-.7 .5M131.6 112.3v.1M131.9 110.8h.2M131.9 111h.2M131.9 111.2h.2M131.9 111.1h.2"/>
<path d="M131.9 112.2h.2M131.9 112.3h.2M131.9 112h.2M131.9 111.9h.2M131.9 111.8h.2M131.9 111.7h.2M131.9 111.6h.2M131.9 111.3h.2M131.9 110.7h.2M131.9 110.6h.2M132.4 110.5h.1M132.4 112.3h.1"/>
<path d="M132.4 112.3l.3 .3 1.2-.1M132.6 107h.1M132.7 110.2l-.3 .3M133.8 110.2l.1 .1 .1-.1M133.8 107h.1M133.9 112.5h.1M134.9 104.6h3.8M135.1 107h4.8M135.1 104.7h3.6M135.1 112.5h4.7M135.2 106.8h4.7M135.2 104.8h3.6"/>
<path d="M135.3 112.4h4.5M135.3 106.7h4.7M135.4 104.9h3.6M135.4 112.3h4.4M135.4 112.2h4.4M135.4 106.6h4.7M135.4 106.5h4.9M135.4 106.4h5M135.4 106.3h5.1M135.4 106.1h5.1M135.4 106h5.1M135.4 105.9h5.1"/>
<path d="M135.4 105.8h5.1M135.4 105.6h4.9M135.4 105.5h4.8M135.4 105.4h4.7M135.4 105.3h4.6M135.4 105.2h4.5M135.4 105.1h4.3M138.7 104.7v-.2h-3.8l-.1 .1h.3l.3 .4v1.7l-.3 .3-1.2-.1-.1 .1-1.2-.1-.1 .1-1.2-.1-1.1 .1-.4-.3v-.3l-5.7-.1-.4-.3M138.7 102.4v.2h-4.4l-.3 .1-1.6 1.8h-.6l-.5 .2-.4-.2h-4.2l-.2-.2M138.7 102.4l.4-.3h2l.4 .3M138.7 104.7l.4 .3h.6l.8 .9M139.4 110l-.2 .2h-16"/>
<path d="M139.8 112.2l-4.4-.1-.3 .5-1.2-.1M139.8 112.2v.4l.2 .4M140.5 105.9v.4l-.5 .4M141.2 102.2h16.8M141.4 102.3h16.6M141.5 102.4h.4M141.5 103.2h.3M141.5 102.4v1.7M141.5 103.6h7.9M141.5 103.5h8M141.5 104.1h.3M141.5 104h.3"/>
<path d="M141.5 103.8h.3M141.5 103.7h.3M141.5 103.4h.3M141.5 103.1h.3M141.5 103h.3M141.5 102.9h.3M141.5 102.8h.3M141.5 102.6h.3M141.5 102.5h.3M141.6 104.2h.2M141.8 104.3h.1M141.8 103.6v.8l-.3-.3"/>
<path d="M141.8 102.5v1M141.9 102.4l.9-.1v2.5h-.6l.1 .1M141.9 102.4l-.1 .1M142.2 104.8h8.1M142.3 104.9h15.7M142.3 104.9l.2 .4M142.4 113.5h6.4M142.4 105.1h6.4M142.4 105.2h6.4M142.5 105.3v1a1.13 1.13 0 0 1 .7 1.2 1.13 1.13 0 0 1-.9 1h-1.6a1.16 1.16 0 0 1-.7-1.8M142.5 106.3h7.1M142.5 106.1h7"/>
<path d="M142.5 106h6.8M142.5 105.9h6.7M142.5 105.8h6.6M142.5 105.6h6.5M142.5 105.5h6.3M142.5 105.4h6.3M142.5 105.3h6.3M142.5 108.4h6M142.6 106.4h7.1M142.7 108.3h5.8M142.8 106.5h15.2M142.8 103.2h.2"/>
<path d="M142.8 104.7h.2M142.8 104.6h.2M142.8 104.4h.2M142.8 104.3h.2M142.8 104.2h.2M142.8 104.1h.2M142.8 104h.2M142.8 103.8h.2M142.8 103.7h.2M142.8 103.4h.2M142.8 103.1h.2M142.8 103h.2"/>
<path d="M142.8 102.9h.2M142.8 102.8h.2M142.8 102.6h.2M142.8 102.5h.2M142.8 102.4h.2M142.9 108.2h5.6M142.9 106.6h15.1M143 108.1h5.5M143 106.7h15M143.1 107.9h5.4M143.1 106.8h6.4M143.1 107.8h5.5"/>
<path d="M143.1 107h6.3M143.2 107.7h5.5M143.2 107.1h6.1M143.2 107.6h5.6M143.2 107.5h5.7M143.2 107.3h5.9M143.2 107.2h6M143.9 102.4l-.9-.1v2.5h.7l.3-.2M143.9 102.4l.1 .1M143.9 102.4h14.1M143.9 104.7h4.9M144 102.5v1"/>
<path d="M144 104.6h4.8M144 102.5h14M144 103.2h14M144 103.6v1M144 104.4h4.8M144 104.3h4.8M144 104.2h4.8M144 104.1h4.9M144 104h5M144 103.8h5.1M144 103.7h5.2M144 103.4h5.6"/>
<path d="M144 103.1h14M144 103h14M144 102.9h14M144 102.8h14M144 102.6h14M149.7 103.2l-.9 1v.5h3.2v-.5l-1-1M150.3 103.2v3.2h-.6l-.9-.9v-.6M150.3 103.6h.2M150.3 103.5h.2M150.3 106.4h.2M150.3 106.3h.2M150.3 106.1h.2"/>
<path d="M150.3 106h.2M150.3 105.9h.2M150.3 105.8h.2M150.3 105.6h.2M150.3 105.5h.2M150.3 105.4h.2M150.3 105.3h.2M150.3 105.2h.2M150.3 105.1h.2M150.3 104.7h.2M150.3 104.6h.2M150.3 104.4h.2"/>
<path d="M150.3 104.3h.2M150.3 104.2h.2M150.3 104.1h.2M150.3 104h.2M150.3 103.8h.2M150.3 103.7h.2M150.3 103.4h.2M150.5 103.2v3.2h.5l1-.9v-.6M150.5 104.8h7.5M151.1 106.4h6.9M151.2 110.6h6.8M151.2 103.4h6.8"/>
<path d="M151.2 106.3h6.8M151.2 114.2h6.8M151.3 106.8h6.7M151.3 110.4h6.7M151.3 110.7h6.7M151.3 103.5h6.7M151.3 106.1h6.7M151.4 114.1h6.6M151.4 107h6.6M151.4 110.2h6.6M151.4 110.8h6.6M151.4 103.6h6.6"/>
<path d="M151.4 106h6.6M151.5 114h6.5M151.5 107.1h6.5M151.5 111h6.5M151.5 110.1h6.5M151.6 103.7h6.4M151.6 105.9h6.4M151.6 113.9h6.4M151.6 107.2h6.4M151.6 110h6.4M151.7 111.1h6.3M151.7 103.8h6.3"/>
<path d="M151.7 105.8h6.3M151.7 113.7h6.3M151.7 107.3h6.3M151.8 109.9h6.2M151.8 111.2h6.2M151.8 104h6.2M151.8 113.6h6.2M151.8 105.6h6.2M151.8 107.5h6.2M151.9 111.3h6.1M151.9 109.7h6.1M151.9 104.1h6.1"/>
<path d="M151.9 105.5h6.1M152 113.5h6M152 107.6h6M152 109.6h6M152 105.4h6M152 105.3h6M152 105.2h6M152 105.1h6M152 104.7h6M152 104.6h6M152 104.4h6M152 104.3h6"/>
<path d="M152 104.2h6M152 111.4h6M152.1 113.4h5.9M152.1 107.7h5.9M152.1 109.5h5.9M152.1 111.6h5.9M152.2 113.2h5.8M152.2 107.8h5.8M152.3 109.4v-1.5l-1.1-1.1h-1.6l-1.1 1.1v1.2l-.4 .5h-8.1l-.6 .4M152.3 111.7v1.5l-1.1 1.1h-1.6l-.9-.9h-6.1l-.3 .1h-1.6l-.7-.5M152.3 112.8h5.7M152.3 109.4l-1.1 1.1"/>
<path d="M152.3 108.8h5.7M152.3 112.5h5.7M152.3 112.2h5.7M152.3 113.1h5.7M152.3 113h5.7M152.3 112.9h5.7M152.3 112.6h5.7M152.3 112.4h5.7M152.3 112.3h5.7M152.3 112h5.7M152.3 111.9h5.7M152.3 111.8h5.7"/>
<path d="M152.3 111.7h5.7M152.3 109.4h5.7M152.3 109.3h5.7M152.3 109.2h5.7M152.3 109h5.7M152.3 108.9h5.7M152.3 108.7h5.7M152.3 108.5h5.7M152.3 108.4h5.7M152.3 108.3h5.7M152.3 108.2h5.7M152.3 108.1h5.7"/>
<path d="M152.3 107.9h5.7M158 110.5h-8.1l-.1 .1h1.4l1.1 1.1M100.7 122.5h57.3M100.7 122.4h57.3M100.7 122.3h57.3M100.7 122.2h57.3M100.7 122h57.3M100.7 121.9h57.3M100.7 121.8h57.3M100.7 121.7h57.3M100.7 121.6h57.3M100.7 121.5h57.3"/>
<path d="M100.7 121.3h57.3M100.7 121.2h57.3M100.7 121.1h57.3M100.7 121h57.3M100.7 120.8h57.3M100.7 120.7h57.3M100.7 120.6h57.3M100.7 120.5h57.3M100.7 120.4h57.3M100.7 120.2h57.3M100.7 120.1h57.3"/>
</g>
<circle cx="150.4" cy="82" r=".55" fill="#fff" stroke="#000" stroke-width=".2"/>
<circle cx="150.4" cy="74.4" r="1.38" fill="#000" stroke="#000" stroke-width=".2"/>
<circle cx="150.4" cy="74.4" r=".55" fill="#fff" stroke="#000" stroke-width=".2"/>
<path d="M112.9 80.7h1.3" fill="none" stroke="#000" stroke-width="1.3"/>
<circle cx="113.6" cy="80.7" r=".4" fill="#fff" stroke="#000" stroke-width=".2"/>
<path d="M112.9 78.1h1.3" fill="none" stroke="#000" stroke-width="1.3"/>
<circle cx="113.6" cy="78.1" r=".4" fill="#fff" stroke="#000" stroke-width=".2"/>
<circle cx="108.5" cy="83.2" r="1.61" fill="#000" stroke="#000" stroke-width=".2"/>
<circle cx="108.5" cy="83.2" r="1.1" fill="#fff" stroke="#000" stroke-width=".2"/>
<circle cx="108.5" cy="73.1" r="1.61" fill="#000" stroke="#000" stroke-width=".2"/>
<circle cx="108.5" cy="73.1" r="1.1" fill="#fff" stroke="#000" stroke-width=".2"/>
<path d="M140.9 76.9h1.1" fill="none" stroke="#000" stroke-width="1.1"/>
<circle cx="141.5" cy="76.9" r=".3" fill="#fff" stroke="#000" stroke-width=".2"/>
<path d="M140.9 81.9h1.1" fill="none" stroke="#000" stroke-width="1.1"/>
<circle cx="141.5" cy="81.9" r=".3" fill="#fff" stroke="#000" stroke-width=".2"/>
<circle cx="150.4" cy="78.1" r="1.38" fill="#000" stroke="#000" stroke-width=".2"/>
<circle cx="150.4" cy="78.1" r=".55" fill="#fff" stroke="#000" stroke-width=".2"/>
<circle cx="150.4" cy="112.4" r="1.38" fill="#000" stroke="#000" stroke-width=".2"/>
<circle cx="150.4" cy="112.4" r=".55" fill="#fff" stroke="#000" stroke-width=".2"/>
<circle cx="150.4" cy="104.8" r="1.38" fill="#000" stroke="#000" stroke-width=".2"/>
<circle cx="150.4" cy="104.8" r=".55" fill="#fff" stroke="#000" stroke-width=".2"/>
<path d="M112.9 111.2h1.3" fill="none" stroke="#000" stroke-width="1.3"/>
<circle cx="113.6" cy="111.2" r=".4" fill="#fff" stroke="#000" stroke-width=".2"/>
<path d="M112.9 108.6h1.3" fill="none" stroke="#000" stroke-width="1.3"/>
<circle cx="113.6" cy="108.6" r=".4" fill="#fff" stroke="#000" stroke-width=".2"/>
<circle cx="108.5" cy="113.7" r="1.61" fill="#000" stroke="#000" stroke-width=".2"/>
<circle cx="108.5" cy="113.7" r="1.1" fill="#fff" stroke="#000" stroke-width=".2"/>
<circle cx="108.5" cy="103.5" r="1.61" fill="#000" stroke="#000" stroke-width=".2"/>
<circle cx="108.5" cy="103.5" r="1.1" fill="#fff" stroke="#000" stroke-width=".2"/>
<path d="M140.9 107.4h1.1" fill="none" stroke="#000" stroke-width="1.1"/>
<circle cx="141.5" cy="107.4" r=".3" fill="#fff" stroke="#000" stroke-width=".2"/>
<path d="M140.9 112.4h1.1" fill="none" stroke="#000" stroke-width="1.1"/>
<circle cx="141.5" cy="112.4" r=".3" fill="#fff" stroke="#000" stroke-width=".2"/>
<circle cx="150.4" cy="108.6" r="1.38" fill="#000" stroke="#000" stroke-width=".2"/>
<circle cx="150.4" cy="108.6" r=".55" fill="#fff" stroke="#000" stroke-width=".2"/>
</svg>
